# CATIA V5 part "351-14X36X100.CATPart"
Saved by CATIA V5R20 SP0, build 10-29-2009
Part number: 351-14X36X100
Definition: NONE
Nomenclature: 351-14X36X100
Source: Unknown
Description: 351-14X36X100
Bounding box of the stored display mesh (mm): x -5 to 95, y -12 to 12, z -12 to 12
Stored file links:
  C:\Users\Utente\Desktop\IO LAVORO\3D X SITO CF\X SITO\PLASTICA\351\351-14X36X100.CATPart

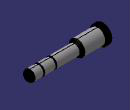
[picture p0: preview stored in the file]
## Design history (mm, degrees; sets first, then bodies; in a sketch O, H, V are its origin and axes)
Body1 "351-14X36X100" (main body)
  Solid1: solid without history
